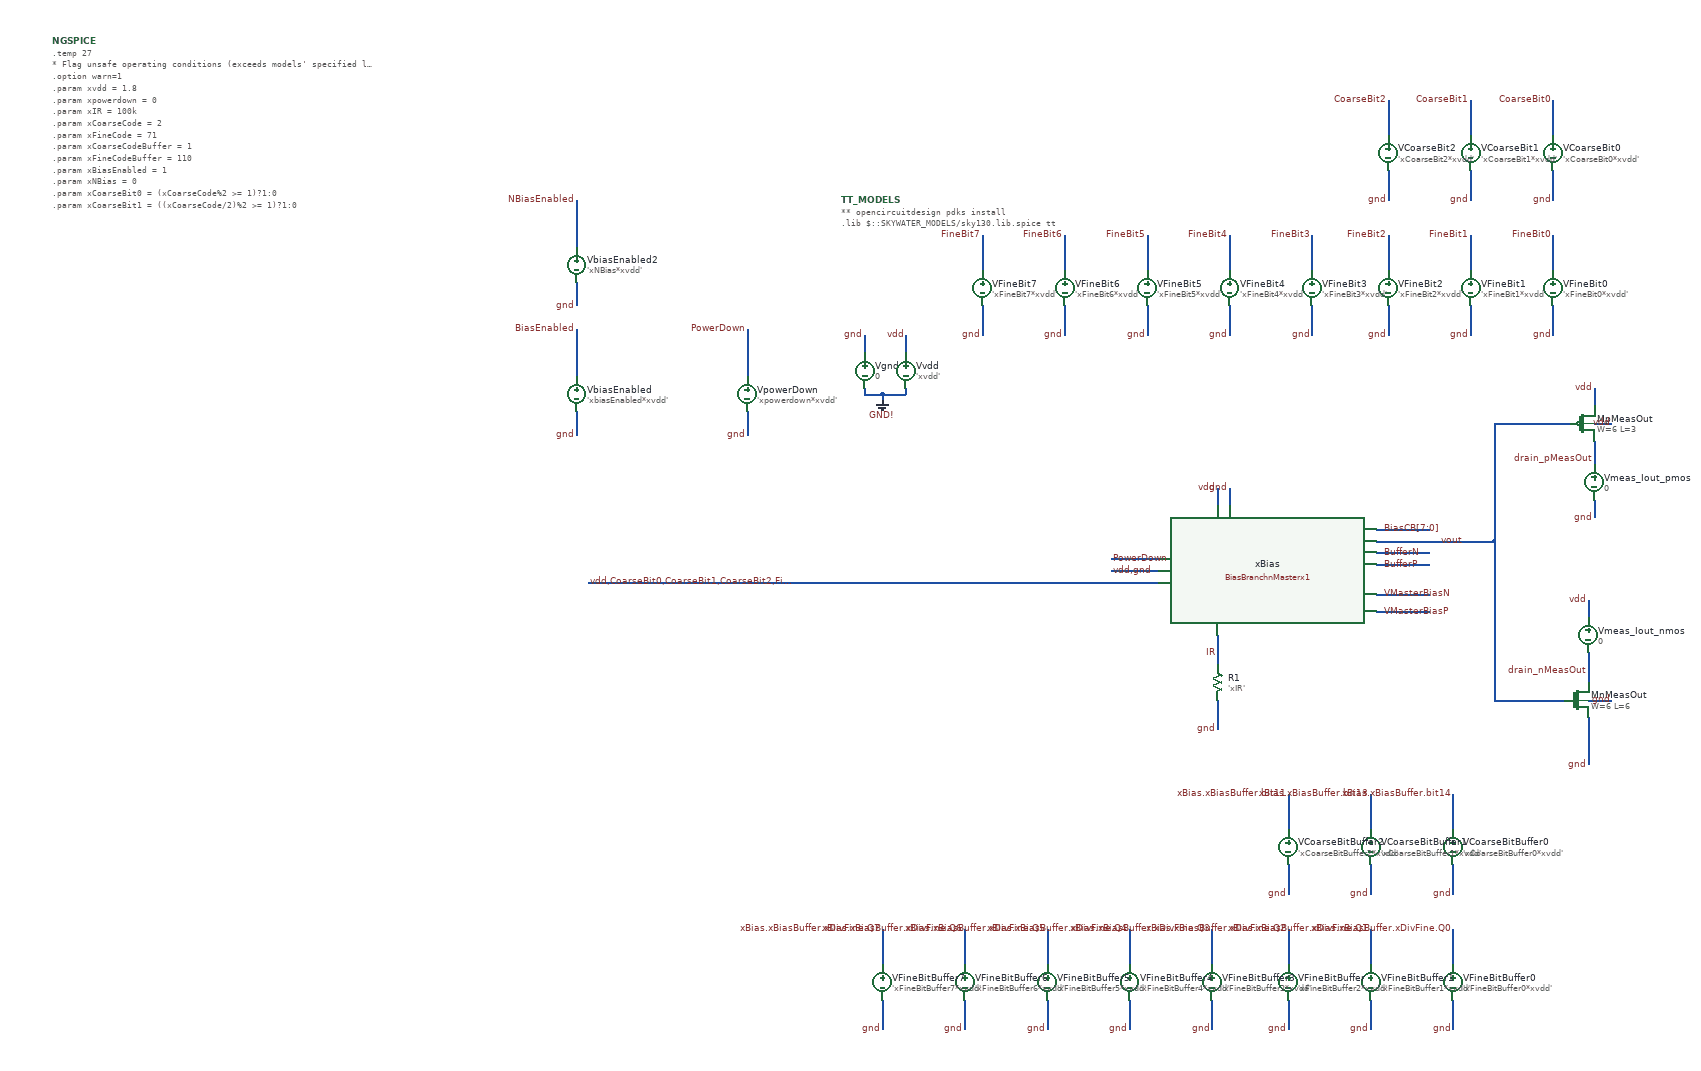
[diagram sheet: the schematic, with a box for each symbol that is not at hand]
v {xschem version=3.4.8RC file_version=1.3}
G {}
K {}
V {}
S {}
F {}
E {}
N 1250 -890 1250 -880 {lab=GND!}
N 1210 -880 1250 -880 {lab=GND!}
N 1180 -890 1180 -880 {lab=GND!}
N 1210 -880 1210 -870 {lab=GND!}
N 1180 -880 1210 -880 {lab=GND!}
N 1180 -980 1180 -950 {lab=gnd}
N 1250 -980 1250 -950 {lab=vdd}
N 980 -850 980 -810 {lab=gnd}
N 980 -990 980 -910 {lab=PowerDown}
N 2350 -1260 2350 -1210 {lab=gnd}
N 2350 -1380 2350 -1320 {lab=CoarseBit0}
N 2210 -1260 2210 -1210 {lab=gnd}
N 2210 -1380 2210 -1320 {lab=CoarseBit1}
N 2070 -1260 2070 -1210 {lab=gnd}
N 2070 -1380 2070 -1320 {lab=CoarseBit2}
N 2410 -360 2450 -360 {lab=gnd}
N 2410 -330 2410 -250 {lab=gnd}
N 2050 -630 2250 -630 {lab=vout}
N 2250 -630 2250 -360 {lab=vout}
N 2250 -360 2370 -360 {lab=vout}
N 2410 -440 2410 -390 {lab=drain_nMeasOut}
N 2410 -530 2410 -500 {lab=vdd}
N 2250 -830 2250 -630 {lab=vout}
N 2250 -830 2380 -830 {lab=vout}
N 2420 -700 2420 -670 {lab=gnd}
N 2420 -800 2420 -760 {lab=drain_pMeasOut}
N 2420 -890 2420 -860 {lab=vdd}
N 2420 -830 2450 -830 {lab=vdd}
N 1780 -720 1780 -690 {lab=vdd}
N 1800 -720 1800 -690 {lab=gnd}
N 690 -850 690 -810 {lab=gnd}
N 690 -990 690 -910 {lab=BiasEnabled}
N 690 -1070 690 -1030 {lab=gnd}
N 690 -1210 690 -1130 {lab=NBiasEnabled}
N 2050 -650 2140 -650 {lab=BiasCB[7:0]}
N 2050 -610 2140 -610 {lab=BufferN}
N 2050 -590 2140 -590 {lab=BufferP}
N 2050 -540 2140 -540 {lab=VMasterBiasN}
N 2050 -510 2140 -510 {lab=VMasterBiasP}
N 1600 -600 1680 -600 {lab=PowerDown}
N 1600 -580 1680 -580 {lab=vdd,gnd}
N 1780 -470 1780 -420 {lab=IR}
N 1780 -360 1780 -310 {lab=gnd}
N 2350 -1030 2350 -980 {lab=gnd}
N 2350 -1150 2350 -1090 {lab=FineBit0}
N 2210 -1030 2210 -980 {lab=gnd}
N 2210 -1150 2210 -1090 {lab=FineBit1}
N 2070 -1030 2070 -980 {lab=gnd}
N 2070 -1150 2070 -1090 {lab=FineBit2}
N 1940 -1030 1940 -980 {lab=gnd}
N 1940 -1150 1940 -1090 {lab=FineBit3}
N 1800 -1030 1800 -980 {lab=gnd}
N 1800 -1150 1800 -1090 {lab=FineBit4}
N 1660 -1030 1660 -980 {lab=gnd}
N 1660 -1150 1660 -1090 {lab=FineBit5}
N 1520 -1030 1520 -980 {lab=gnd}
N 1520 -1150 1520 -1090 {lab=FineBit6}
N 1380 -1030 1380 -980 {lab=gnd}
N 1380 -1150 1380 -1090 {lab=FineBit7}
N 710 -560 1680 -560 {lab=vdd,CoarseBit0,CoarseBit1,CoarseBit2,FineBit7,FineBit6,FineBit5,FineBit4,FineBit3,FineBit2,FineBit1,FineBit0,gnd,gnd,NBiasEnabled,BiasEnabled}
N 2180 -80 2180 -30 {lab=gnd}
N 2180 -200 2180 -140 {lab=xBias.xBiasBuffer.bit14}
N 2040 -80 2040 -30 {lab=gnd}
N 2040 -200 2040 -140 {lab=xBias.xBiasBuffer.bit13}
N 1900 -80 1900 -30 {lab=gnd}
N 1900 -200 1900 -140 {lab=xBias.xBiasBuffer.bit11}
N 2180 150 2180 200 {lab=gnd}
N 2180 30 2180 90 {lab=xBias.xBiasBuffer.xDivFine.Q0}
N 2040 150 2040 200 {lab=gnd}
N 2040 30 2040 90 {lab=xBias.xBiasBuffer.xDivFine.Q1}
N 1900 150 1900 200 {lab=gnd}
N 1900 30 1900 90 {lab=xBias.xBiasBuffer.xDivFine.Q2}
N 1770 150 1770 200 {lab=gnd}
N 1770 30 1770 90 {lab=xBias.xBiasBuffer.xDivFine.Q3}
N 1630 150 1630 200 {lab=gnd}
N 1630 30 1630 90 {lab=xBias.xBiasBuffer.xDivFine.Q4}
N 1490 150 1490 200 {lab=gnd}
N 1490 30 1490 90 {lab=xBias.xBiasBuffer.xDivFine.Q5}
N 1350 150 1350 200 {lab=gnd}
N 1350 30 1350 90 {lab=xBias.xBiasBuffer.xDivFine.Q6}
N 1210 150 1210 200 {lab=gnd}
N 1210 30 1210 90 {lab=xBias.xBiasBuffer.xDivFine.Q7}
C {vsource.sym} 1180 -920 0 0 {name=Vgnd value=0 savecurrent=true}
C {gnd.sym} 1210 -870 0 0 {name=l1 lab=GND!}
C {vsource.sym} 1250 -920 0 0 {name=Vvdd value='xvdd' savecurrent=true}
C {lab_wire.sym} 1180 -980 3 0 {name=p1 sig_type=std_logic lab=gnd}
C {lab_wire.sym} 1250 -980 3 0 {name=p4 sig_type=std_logic lab=vdd}
C {vsource.sym} 980 -880 0 0 {name=VpowerDown value='xpowerdown*xvdd' savecurrent=true}
C {lab_wire.sym} 980 -810 3 1 {name=p7 sig_type=std_logic lab=gnd}
C {lab_wire.sym} 980 -990 3 0 {name=p8 sig_type=std_logic lab=PowerDown}
C {devices/code.sym} 1140 -1210 0 0 {name=TT_MODELS
only_toplevel=true
format="tcleval( @value )"
value="
** opencircuitdesign pdks install
.lib $::SKYWATER_MODELS/sky130.lib.spice tt
"
spice_ignore=false}
C {devices/launcher.sym} 1120 -1340 2 1 {name=h1
descr="Annotate OP" 
tclcommand="set show_hidden_texts 1; xschem annotate_op"
}
C {code_shown.sym} -200 -1480 0 0 {name=NGSPICE
only_toplevel=true
value="

.temp 27

* Flag unsafe operating conditions (exceeds models' specified limits)
.option warn=1

.param xvdd = 1.8
.param xpowerdown = 0
.param xIR = 100k

.param xCoarseCode = 2
.param xFineCode = 71
.param xCoarseCodeBuffer = 1
.param xFineCodeBuffer = 110


.param xBiasEnabled = 1
.param xNBias = 0

.param xCoarseBit0 = (xCoarseCode%2 >= 1)?1:0
.param xCoarseBit1 = ((xCoarseCode/2)%2 >= 1)?1:0
.param xCoarseBit2 = ((xCoarseCode/4)%2 >= 1)?1:0
.param xFineBit0 = (xFineCode%2 >= 1)?1:0
.param xFineBit1 = ((xFineCode/2)%2 >= 1)?1:0
.param xFineBit2 = ((xFineCode/4)%2 >= 1)?1:0
.param xFineBit3 = ((xFineCode/8)%2 >= 1)?1:0
.param xFineBit4 = ((xFineCode/16)%2 >= 1)?1:0
.param xFineBit5 = ((xFineCode/32)%2 >= 1)?1:0
.param xFineBit6 = ((xFineCode/64)%2 >= 1)?1:0
.param xFineBit7 = ((xFineCode/128)%2 >= 1)?1:0

.param xCoarseBitBuffer0 = (xCoarseCodeBuffer%2 >= 1)?1:0
.param xCoarseBitBuffer1 = ((xCoarseCodeBuffer/2)%2 >= 1)?1:0
.param xCoarseBitBuffer2 = ((xCoarseCodeBuffer/4)%2 >= 1)?1:0
.param xFineBitBuffer0 = (xFineCodeBuffer%2 >= 1)?1:0
.param xFineBitBuffer1 = ((xFineCodeBuffer/2)%2 >= 1)?1:0
.param xFineBitBuffer2 = ((xFineCodeBuffer/4)%2 >= 1)?1:0
.param xFineBitBuffer3 = ((xFineCodeBuffer/8)%2 >= 1)?1:0
.param xFineBitBuffer4 = ((xFineCodeBuffer/16)%2 >= 1)?1:0
.param xFineBitBuffer5 = ((xFineCodeBuffer/32)%2 >= 1)?1:0
.param xFineBitBuffer6 = ((xFineCodeBuffer/64)%2 >= 1)?1:0
.param xFineBitBuffer7 = ((xFineCodeBuffer/128)%2 >= 1)?1:0

*.nodeset v(xBias.xBiasBuffer.bit14) = 'xCoarseBitBuffer0*xvdd'
*.nodeset v(xBias.xBiasBuffer.bit13) = 'xCoarseBitBuffer1*xvdd'
*.nodeset v(xBias.xBiasBuffer.bit12) = 'xCoarseBitBuffer0*xvdd'
*.nodeset v(xBias.xBiasBuffer.xDivFine.Q7) = 'xFineBitBuffer7*xvdd'
*.nodeset v(xBias.xBiasBuffer.xDivFine.Q6) = 'xFineBitBuffer6*xvdd'
*.nodeset v(xBias.xBiasBuffer.xDivFine.Q5) = 'xFineBitBuffer5*xvdd'
*.nodeset v(xBias.xBiasBuffer.xDivFine.Q4) = 'xFineBitBuffer4*xvdd'
*.nodeset v(xBias.xBiasBuffer.xDivFine.Q3) = 'xFineBitBuffer3*xvdd'
*.nodeset v(xBias.xBiasBuffer.xDivFine.Q2) = 'xFineBitBuffer2*xvdd'
*.nodeset v(xBias.xBiasBuffer.xDivFine.Q1) = 'xFineBitBuffer1*xvdd'
*.nodeset v(xBias.xBiasBuffer.xDivFine.Q0) = 'xFineBitBuffer0*xvdd'



.save v(@m.xBias.xBiasMasternCoarse.xBiasMasterBias.xMNBias.msky130_fd_pr__nfet_01v8_lvt[vdsat])
.save @m.xBias.xBiasMasternCoarse.xBiasMasterBias.xMNBias.msky130_fd_pr__nfet_01v8_lvt[id]
.save v(@m.xBias.xBiasMasternCoarse.xBiasMasterBias.xMNBiasDio.msky130_fd_pr__nfet_01v8_lvt[vdsat])
.save @m.xBias.xBiasMasternCoarse.xBiasMasterBias.xMNBiasDio.msky130_fd_pr__nfet_01v8_lvt[id]
.save v(@m.xBias.xBiasMasternCoarse.xBiasMasterBias.xMNBiasCascDio.msky130_fd_pr__nfet_01v8_lvt[vdsat])
.save v(@m.xBias.xBiasMasternCoarse.xBiasMasterBias.xMNBiasCasc.msky130_fd_pr__nfet_01v8_lvt[vdsat])
.save v(@m.xBias.xBiasMasternCoarse.xBiasMasterBias.xMPBias.msky130_fd_pr__pfet_01v8_lvt[vdsat])
.save v(@m.xBias.xBiasMasternCoarse.xBiasMasterBias.xMPBiasDio.msky130_fd_pr__pfet_01v8_lvt[vdsat])
.save v(@m.xBias.xBiasMasternCoarse.xBiasMasterBias.xMNMirr1.msky130_fd_pr__nfet_01v8_lvt[vdsat])
.save @m.xBias.xBiasMasternCoarse.xBiasMasterBias.xMNMirr1.msky130_fd_pr__nfet_01v8_lvt[id]
.save v(@m.xBias.xBiasMasternCoarse.xBiasMasterBias.xMNMirr2.msky130_fd_pr__nfet_01v8_lvt[vdsat])
.save @m.xBias.xBiasMasternCoarse.xBiasMasterBias.xMNMirr2.msky130_fd_pr__nfet_01v8_lvt[id]
.save v(@m.xBias.xBiasMasternCoarse.xBiasMasterBias.xMNMirrCasc1.msky130_fd_pr__nfet_01v8_lvt[vdsat])
.save v(@m.xBias.xBiasMasternCoarse.xBiasMasterBias.xMNMirrCasc2.msky130_fd_pr__nfet_01v8_lvt[vdsat])
.save @m.xBias.xBiasMasternCoarse.xMBDiv.xMNDioCB0.msky130_fd_pr__nfet_01v8_lvt[id]
.save @m.xBias.xBiasMasternCoarse.xMBDiv.xMNDioCB1.msky130_fd_pr__nfet_01v8_lvt[id]
.save @m.xBias.xBiasMasternCoarse.xMBDiv.xMNDioCB2.msky130_fd_pr__nfet_01v8_lvt[id]
.save @m.xBias.xBiasMasternCoarse.xMBDiv.xMNDioCB3.msky130_fd_pr__nfet_01v8_lvt[id]
.save @m.xBias.xBiasMasternCoarse.xMBDiv.xMNDioCB4.msky130_fd_pr__nfet_01v8_lvt[id]
.save @m.xBias.xBiasMasternCoarse.xMBDiv.xMNDioCB5.msky130_fd_pr__nfet_01v8_lvt[id]
.save @m.xBias.xBiasMasternCoarse.xMBDiv.xMNDioCB6.msky130_fd_pr__nfet_01v8_lvt[id]
.save @m.xBias.xBiasMasternCoarse.xMBDiv.xMNDioCB7.msky130_fd_pr__nfet_01v8_lvt[id]
.save @m.xBias.xBiasBranch.xCoarseBuf.xSel.xMmirrB0.msky130_fd_pr__nfet_01v8_lvt[id]
.save @m.xBias.xBiasBranch.xCoarseBuf.xSel.xMmirrB1.msky130_fd_pr__nfet_01v8_lvt[id]
.save @m.xBias.xBiasBranch.xCoarseBuf.xSel.xMmirrhB2.msky130_fd_pr__nfet_01v8_lvt[id]
.save @m.xBias.xBiasBranch.xCoarseBuf.xSel.xMmirrhB3.msky130_fd_pr__nfet_01v8_lvt[id]
.save @m.xBias.xBiasBranch.xCoarseBuf.xSel.xMmirrhB4t07.msky130_fd_pr__nfet_01v8_lvt[id]
.save v(@m.xBias.xBiasBranch.xCoarseBuf.xSel.xMmirrB0.msky130_fd_pr__nfet_01v8_lvt[vdsat])
.save v(@m.xBias.xBiasBranch.xCoarseBuf.xSel.xMmirrB1.msky130_fd_pr__nfet_01v8_lvt[vdsat])
.save v(@m.xBias.xBiasBranch.xCoarseBuf.xSel.xMmirrhB2.msky130_fd_pr__nfet_01v8_lvt[vdsat])
.save v(@m.xBias.xBiasBranch.xCoarseBuf.xSel.xMmirrhB3.msky130_fd_pr__nfet_01v8_lvt[vdsat])
.save v(@m.xBias.xBiasBranch.xCoarseBuf.xSel.xMmirrhB4t07.msky130_fd_pr__nfet_01v8_lvt[vdsat])
.save @m.xBias.xBiasBranch.xCoarse2Fine.xMpDioOut.msky130_fd_pr__pfet_01v8_lvt[id]
.save @m.xBias.xBiasBranch.xCoarse2Fine.xMpMirrOut.msky130_fd_pr__pfet_01v8_lvt[id]
.save @m.xBias.xBiasBranch.xCoarse2Fine.xMpDionOut2.msky130_fd_pr__pfet_01v8_lvt[id]
.save @m.xBias.xBiasBranch.xCoarse2Fine.xMpMirrnOut2.msky130_fd_pr__pfet_01v8_lvt[id]
.save v(@m.xBias.xBiasBranch.xCoarse2Fine.xMpDioOut.msky130_fd_pr__pfet_01v8_lvt[vdsat])
.save v(@m.xBias.xBiasBranch.xCoarse2Fine.xMpMirrOut.msky130_fd_pr__pfet_01v8_lvt[vdsat])
.save v(@m.xBias.xBiasBranch.xCoarse2Fine.xMpDionOut2.msky130_fd_pr__pfet_01v8_lvt[vdsat])
.save v(@m.xBias.xBiasBranch.xCoarse2Fine.xMpMirrnOut2.msky130_fd_pr__pfet_01v8_lvt[vdsat])
.save @m.xBias.xBiasBranch.xCoarse2Fine.xMpInDio.msky130_fd_pr__pfet_01v8_lvt[id]
.save @m.xBias.xBiasBranch.xBuffs.xMnDio.msky130_fd_pr__nfet_01v8[id]
.save @m.xBias.xBiasBranch.xBuffs.xMnMirr.msky130_fd_pr__nfet_01v8[id]
.save @m.xBias.xBiasBranch.xBuffs.xMnMirrBuffBias.msky130_fd_pr__nfet_01v8_lvt[id]
.save @m.xBias.xBiasBranch.xBuffs.xMnMirrBuffB0.msky130_fd_pr__nfet_01v8_lvt[id]
.save @m.xBias.xBiasBranch.xBuffs.xMnMirrBuffnB0.msky130_fd_pr__nfet_01v8_lvt[id]
.save v(@m.xBias.xBiasBranch.xBuffs.xMnDio.msky130_fd_pr__nfet_01v8[vdsat])
.save v(@m.xBias.xBiasBranch.xBuffs.xMnMirr.msky130_fd_pr__nfet_01v8[vdsat])
.save v(@m.xBias.xBiasBranch.xBuffs.xMnMirrBuffBias.msky130_fd_pr__nfet_01v8_lvt[vdsat])
.save v(@m.xBias.xBiasBranch.xBuffs.xMnMirrBuffB0.msky130_fd_pr__nfet_01v8_lvt[vdsat])
.save v(@m.xBias.xBiasBranch.xBuffs.xMnMirrBuffnB0.msky130_fd_pr__nfet_01v8_lvt[vdsat])
.save @m.xBias.xBiasBranch.xBuffs.xMpDio.msky130_fd_pr__pfet_01v8[id]
.save @m.xBias.xBiasBranch.xBuffs.xMpMirrBuffBias.msky130_fd_pr__pfet_01v8_lvt[id]
.save @m.xBias.xBiasBranch.xBuffs.xMpMirrBuffB0.msky130_fd_pr__pfet_01v8_lvt[id]
.save @m.xBias.xBiasBranch.xBuffs.xMpMirrBuffnB0.msky130_fd_pr__pfet_01v8_lvt[id]
.save v(@m.xBias.xBiasBranch.xBuffs.xMpDio.msky130_fd_pr__pfet_01v8[vdsat])
.save v(@m.xBias.xBiasBranch.xBuffs.xMpMirrBuffBias.msky130_fd_pr__pfet_01v8_lvt[vdsat])
.save v(@m.xBias.xBiasBranch.xBuffs.xMpMirrBuffB0.msky130_fd_pr__pfet_01v8_lvt[vdsat])
.save v(@m.xBias.xBiasBranch.xBuffs.xMpMirrBuffnB0.msky130_fd_pr__pfet_01v8_lvt[vdsat])
.save @m.xBias.xBiasBuffer.xCoarseBuf.xSel.xMmirrB0.msky130_fd_pr__nfet_01v8_lvt[id]
.save @m.xBias.xBiasBuffer.xCoarseBuf.xSel.xMmirrB1.msky130_fd_pr__nfet_01v8_lvt[id]
.save @m.xBias.xBiasBuffer.xCoarseBuf.xSel.xMmirrhB2.msky130_fd_pr__nfet_01v8_lvt[id]
.save @m.xBias.xBiasBuffer.xCoarseBuf.xSel.xMmirrhB3.msky130_fd_pr__nfet_01v8_lvt[id]
.save @m.xBias.xBiasBuffer.xCoarseBuf.xSel.xMmirrhB4t07.msky130_fd_pr__nfet_01v8_lvt[id]
.save v(@m.xBias.xBiasBuffer.xCoarseBuf.xSel.xMmirrB0.msky130_fd_pr__nfet_01v8_lvt[vdsat])
.save v(@m.xBias.xBiasBuffer.xCoarseBuf.xSel.xMmirrB1.msky130_fd_pr__nfet_01v8_lvt[vdsat])
.save v(@m.xBias.xBiasBuffer.xCoarseBuf.xSel.xMmirrhB2.msky130_fd_pr__nfet_01v8_lvt[vdsat])
.save v(@m.xBias.xBiasBuffer.xCoarseBuf.xSel.xMmirrhB3.msky130_fd_pr__nfet_01v8_lvt[vdsat])
.save v(@m.xBias.xBiasBuffer.xCoarseBuf.xSel.xMmirrhB4t07.msky130_fd_pr__nfet_01v8_lvt[vdsat])
.save @m.xBias.xBiasBuffer.xCoarse2Fine.xMpDioOut.msky130_fd_pr__pfet_01v8_lvt[id]
.save @m.xBias.xBiasBuffer.xCoarse2Fine.xMpMirrOut.msky130_fd_pr__pfet_01v8_lvt[id]
.save @m.xBias.xBiasBuffer.xCoarse2Fine.xMpDionOut2.msky130_fd_pr__pfet_01v8_lvt[id]
.save @m.xBias.xBiasBuffer.xCoarse2Fine.xMpMirrnOut2.msky130_fd_pr__pfet_01v8_lvt[id]
.save v(@m.xBias.xBiasBuffer.xCoarse2Fine.xMpDioOut.msky130_fd_pr__pfet_01v8_lvt[vdsat])
.save v(@m.xBias.xBiasBuffer.xCoarse2Fine.xMpMirrOut.msky130_fd_pr__pfet_01v8_lvt[vdsat])
.save v(@m.xBias.xBiasBuffer.xCoarse2Fine.xMpDionOut2.msky130_fd_pr__pfet_01v8_lvt[vdsat])
.save v(@m.xBias.xBiasBuffer.xCoarse2Fine.xMpMirrnOut2.msky130_fd_pr__pfet_01v8_lvt[vdsat])
.save @m.xBias.xBiasBuffer.xCoarse2Fine.xMpInDio.msky130_fd_pr__pfet_01v8_lvt[id]
.save @m.xBias.xBiasBuffer.xMnDio.msky130_fd_pr__nfet_01v8_lvt[id]
.save @m.xBias.xBiasBuffer.xMnMirr.msky130_fd_pr__nfet_01v8_lvt[id]
.save @m.xBias.xBiasBuffer.xMpDio.msky130_fd_pr__pfet_01v8_lvt[id]
.save v(@m.xBias.xBiasBuffer.xMnDio.msky130_fd_pr__nfet_01v8_lvt[vdsat])
.save v(@m.xBias.xBiasBuffer.xMnMirr.msky130_fd_pr__nfet_01v8_lvt[vdsat])
.save v(@m.xBias.xBiasBuffer.xMpDio.msky130_fd_pr__pfet_01v8_lvt[vdsat])


.save all

.op
"}
C {vsource.sym} 2350 -1290 0 0 {name=VCoarseBit0 value='xCoarseBit0*xvdd' savecurrent=true}
C {lab_wire.sym} 2350 -1210 3 1 {name=p27 sig_type=std_logic lab=gnd}
C {lab_wire.sym} 2350 -1380 1 1 {name=p28 sig_type=std_logic lab=CoarseBit0}
C {vsource.sym} 2210 -1290 0 0 {name=VCoarseBit1 value='xCoarseBit1*xvdd' savecurrent=true}
C {lab_wire.sym} 2210 -1210 3 1 {name=p29 sig_type=std_logic lab=gnd}
C {lab_wire.sym} 2210 -1380 1 1 {name=p30 sig_type=std_logic lab=CoarseBit1}
C {vsource.sym} 2070 -1290 0 0 {name=VCoarseBit2 value='xCoarseBit2*xvdd' savecurrent=true}
C {lab_wire.sym} 2070 -1210 3 1 {name=p31 sig_type=std_logic lab=gnd}
C {lab_wire.sym} 2070 -1380 1 1 {name=p32 sig_type=std_logic lab=CoarseBit2}
C {sky130_fd_pr/nfet_01v8.sym} 2390 -360 0 0 {name=MnMeasOut
W=6
L=6
nf=1 
mult=1
ad="expr('int((@nf + 1)/2) * @W / @nf * 0.29')"
pd="expr('2*int((@nf + 1)/2) * (@W / @nf + 0.29)')"
as="expr('int((@nf + 2)/2) * @W / @nf * 0.29')"
ps="expr('2*int((@nf + 2)/2) * (@W / @nf + 0.29)')"
nrd="expr('0.29 / @W ')" nrs="expr('0.29 / @W ')"
sa=0 sb=0 sd=0
model=nfet_01v8
spiceprefix=X
}
C {lab_wire.sym} 2450 -360 2 1 {name=p42 sig_type=std_logic lab=gnd}
C {lab_wire.sym} 2410 -250 3 1 {name=p43 sig_type=std_logic lab=gnd}
C {vsource.sym} 2410 -470 0 1 {name=Vmeas_Iout_nmos value=0 savecurrent=true}
C {lab_wire.sym} 2410 -530 1 1 {name=p44 sig_type=std_logic lab=vdd}
C {sky130_fd_pr/pfet_01v8.sym} 2400 -830 0 0 {name=MpMeasOut
W=6
L=3
nf=1
mult=2
ad="expr('int((@nf + 1)/2) * @W / @nf * 0.29')"
pd="expr('2*int((@nf + 1)/2) * (@W / @nf + 0.29)')"
as="expr('int((@nf + 2)/2) * @W / @nf * 0.29')"
ps="expr('2*int((@nf + 2)/2) * (@W / @nf + 0.29)')"
nrd="expr('0.29 / @W ')" nrs="expr('0.29 / @W ')"
sa=0 sb=0 sd=0
model=pfet_01v8
spiceprefix=X
}
C {vsource.sym} 2420 -730 0 1 {name=Vmeas_Iout_pmos value=0 savecurrent=true}
C {lab_wire.sym} 2420 -670 3 1 {name=p45 sig_type=std_logic lab=gnd}
C {lab_wire.sym} 2420 -890 1 1 {name=p46 sig_type=std_logic lab=vdd}
C {lab_wire.sym} 2450 -830 2 1 {name=p47 sig_type=std_logic lab=vdd}
C {lab_wire.sym} 2420 -770 3 1 {name=p48 sig_type=std_logic lab=drain_pMeasOut}
C {lab_wire.sym} 1780 -720 3 0 {name=p59 sig_type=std_logic lab=vdd}
C {lab_wire.sym} 1800 -720 3 0 {name=p61 sig_type=std_logic lab=gnd}
C {vsource.sym} 690 -880 0 0 {name=VbiasEnabled value='xbiasEnabled*xvdd' savecurrent=false}
C {lab_wire.sym} 690 -810 3 1 {name=VbiasEnabled1 sig_type=std_logic lab=gnd
value='(1-xbiasEnabled)*xvdd'
savecurrent=false}
C {lab_wire.sym} 690 -990 3 0 {name=p2 sig_type=std_logic lab=BiasEnabled}
C {vsource.sym} 690 -1100 0 0 {name=VbiasEnabled2 value='xNBias*xvdd' savecurrent=false}
C {lab_wire.sym} 690 -1030 3 1 {name=VbiasEnabled5 sig_type=std_logic lab=gnd
value='(1-xbiasEnabled)*xvdd'
savecurrent=false}
C {lab_wire.sym} 690 -1210 3 0 {name=p5 sig_type=std_logic lab=NBiasEnabled}
C {lab_wire.sym} 2200 -630 0 0 {name=p10 sig_type=std_logic lab=vout}
C {lab_wire.sym} 2410 -410 3 1 {name=p11 sig_type=std_logic lab=drain_nMeasOut}
C {BiasBranchnMasterx1.sym} 1520 -560 0 0 {name=xBias}
C {noconn.sym} 2140 -650 2 0 {name=l3[7:0]}
C {lab_wire.sym} 2060 -650 0 1 {name=p12 sig_type=std_logic lab=BiasCB[7:0]}
C {noconn.sym} 2140 -610 2 0 {name=l2}
C {noconn.sym} 2140 -590 2 0 {name=l3}
C {noconn.sym} 2140 -540 2 0 {name=l4}
C {noconn.sym} 2140 -510 2 0 {name=l5}
C {lab_wire.sym} 2060 -610 0 1 {name=p13 sig_type=std_logic lab=BufferN}
C {lab_wire.sym} 2060 -590 0 1 {name=p14 sig_type=std_logic lab=BufferP}
C {lab_wire.sym} 2060 -540 0 1 {name=p15 sig_type=std_logic lab=VMasterBiasN}
C {lab_wire.sym} 2060 -510 0 1 {name=p16 sig_type=std_logic lab=VMasterBiasP}
C {lab_wire.sym} 1600 -600 0 1 {name=p9 sig_type=std_logic lab=PowerDown}
C {lab_wire.sym} 1600 -580 0 1 {name=p17 sig_type=std_logic lab=vdd,gnd}
C {res.sym} 1780 -390 0 0 {name=R1
value='xIR'
footprint=1206
device=resistor
m=1}
C {lab_wire.sym} 1780 -310 3 1 {name=p18 sig_type=std_logic lab=gnd}
C {lab_wire.sym} 1780 -440 3 1 {name=p19 sig_type=std_logic lab=IR}
C {vsource.sym} 2350 -1060 0 0 {name=VFineBit0 value='xFineBit0*xvdd' savecurrent=true}
C {lab_wire.sym} 2350 -980 3 1 {name=p20 sig_type=std_logic lab=gnd}
C {lab_wire.sym} 2350 -1150 1 1 {name=p21 sig_type=std_logic lab=FineBit0}
C {vsource.sym} 2210 -1060 0 0 {name=VFineBit1 value='xFineBit1*xvdd' savecurrent=true}
C {lab_wire.sym} 2210 -980 3 1 {name=p22 sig_type=std_logic lab=gnd}
C {lab_wire.sym} 2210 -1150 1 1 {name=p23 sig_type=std_logic lab=FineBit1}
C {vsource.sym} 2070 -1060 0 0 {name=VFineBit2 value='xFineBit2*xvdd' savecurrent=true}
C {lab_wire.sym} 2070 -980 3 1 {name=p24 sig_type=std_logic lab=gnd}
C {lab_wire.sym} 2070 -1150 1 1 {name=p25 sig_type=std_logic lab=FineBit2}
C {vsource.sym} 1940 -1060 0 0 {name=VFineBit3 value='xFineBit3*xvdd' savecurrent=true}
C {lab_wire.sym} 1940 -980 3 1 {name=p26 sig_type=std_logic lab=gnd}
C {lab_wire.sym} 1940 -1150 1 1 {name=p33 sig_type=std_logic lab=FineBit3}
C {vsource.sym} 1800 -1060 0 0 {name=VFineBit4 value='xFineBit4*xvdd' savecurrent=true}
C {lab_wire.sym} 1800 -980 3 1 {name=p34 sig_type=std_logic lab=gnd}
C {lab_wire.sym} 1800 -1150 1 1 {name=p35 sig_type=std_logic lab=FineBit4}
C {vsource.sym} 1660 -1060 0 0 {name=VFineBit5 value='xFineBit5*xvdd' savecurrent=true}
C {lab_wire.sym} 1660 -980 3 1 {name=p36 sig_type=std_logic lab=gnd}
C {lab_wire.sym} 1660 -1150 1 1 {name=p37 sig_type=std_logic lab=FineBit5}
C {vsource.sym} 1520 -1060 0 0 {name=VFineBit6 value='xFineBit6*xvdd' savecurrent=true}
C {lab_wire.sym} 1520 -980 3 1 {name=p41 sig_type=std_logic lab=gnd}
C {lab_wire.sym} 1520 -1150 1 1 {name=p49 sig_type=std_logic lab=FineBit6}
C {vsource.sym} 1380 -1060 0 0 {name=VFineBit7 value='xFineBit7*xvdd' savecurrent=true}
C {lab_wire.sym} 1380 -980 3 1 {name=p50 sig_type=std_logic lab=gnd}
C {lab_wire.sym} 1380 -1150 1 1 {name=p51 sig_type=std_logic lab=FineBit7}
C {lab_wire.sym} 710 -560 0 1 {name=p3 sig_type=std_logic lab=vdd,CoarseBit0,CoarseBit1,CoarseBit2,FineBit7,FineBit6,FineBit5,FineBit4,FineBit3,FineBit2,FineBit1,FineBit0,gnd,gnd,NBiasEnabled,BiasEnabled}
C {vsource.sym} 2180 -110 0 0 {name=VCoarseBitBuffer0 value='xCoarseBitBuffer0*xvdd' savecurrent=true}
C {lab_wire.sym} 2180 -30 3 1 {name=p6 sig_type=std_logic lab=gnd}
C {lab_wire.sym} 2180 -200 1 1 {name=p38 sig_type=std_logic lab=xBias.xBiasBuffer.bit14}
C {vsource.sym} 2040 -110 0 0 {name=VCoarseBitBuffer1 value='xCoarseBitBuffer1*xvdd' savecurrent=true}
C {lab_wire.sym} 2040 -30 3 1 {name=p39 sig_type=std_logic lab=gnd}
C {lab_wire.sym} 2040 -200 1 1 {name=p40 sig_type=std_logic lab=xBias.xBiasBuffer.bit13}
C {vsource.sym} 1900 -110 0 0 {name=VCoarseBitBuffer2 value='xCoarseBitBuffer2*xvdd' savecurrent=true}
C {lab_wire.sym} 1900 -30 3 1 {name=p52 sig_type=std_logic lab=gnd}
C {lab_wire.sym} 1900 -200 1 1 {name=p53 sig_type=std_logic lab=xBias.xBiasBuffer.bit11}
C {vsource.sym} 2180 120 0 0 {name=VFineBitBuffer0 value='xFineBitBuffer0*xvdd' savecurrent=true}
C {lab_wire.sym} 2180 200 3 1 {name=p54 sig_type=std_logic lab=gnd}
C {lab_wire.sym} 2180 30 1 1 {name=p55 sig_type=std_logic lab=xBias.xBiasBuffer.xDivFine.Q0}
C {vsource.sym} 2040 120 0 0 {name=VFineBitBuffer1 value='xFineBitBuffer1*xvdd' savecurrent=true}
C {lab_wire.sym} 2040 200 3 1 {name=p56 sig_type=std_logic lab=gnd}
C {lab_wire.sym} 2040 30 1 1 {name=p57 sig_type=std_logic lab=xBias.xBiasBuffer.xDivFine.Q1}
C {vsource.sym} 1900 120 0 0 {name=VFineBitBuffer value='xFineBitBuffer2*xvdd' savecurrent=true}
C {lab_wire.sym} 1900 200 3 1 {name=p58 sig_type=std_logic lab=gnd}
C {lab_wire.sym} 1900 30 1 1 {name=p60 sig_type=std_logic lab=xBias.xBiasBuffer.xDivFine.Q2}
C {vsource.sym} 1770 120 0 0 {name=VFineBitBuffer3 value='xFineBitBuffer3*xvdd' savecurrent=true}
C {lab_wire.sym} 1770 200 3 1 {name=p62 sig_type=std_logic lab=gnd}
C {lab_wire.sym} 1770 30 1 1 {name=p63 sig_type=std_logic lab=xBias.xBiasBuffer.xDivFine.Q3}
C {vsource.sym} 1630 120 0 0 {name=VFineBitBuffer4 value='xFineBitBuffer4*xvdd' savecurrent=true}
C {lab_wire.sym} 1630 200 3 1 {name=p64 sig_type=std_logic lab=gnd}
C {lab_wire.sym} 1630 30 1 1 {name=p65 sig_type=std_logic lab=xBias.xBiasBuffer.xDivFine.Q4}
C {vsource.sym} 1490 120 0 0 {name=VFineBitBuffer5 value='xFineBitBuffer5*xvdd' savecurrent=true}
C {lab_wire.sym} 1490 200 3 1 {name=p66 sig_type=std_logic lab=gnd}
C {lab_wire.sym} 1490 30 1 1 {name=p67 sig_type=std_logic lab=xBias.xBiasBuffer.xDivFine.Q5}
C {vsource.sym} 1350 120 0 0 {name=VFineBitBuffer6 value='xFineBitBuffer6*xvdd' savecurrent=true}
C {lab_wire.sym} 1350 200 3 1 {name=p68 sig_type=std_logic lab=gnd}
C {lab_wire.sym} 1350 30 1 1 {name=p69 sig_type=std_logic lab=xBias.xBiasBuffer.xDivFine.Q6}
C {vsource.sym} 1210 120 0 0 {name=VFineBitBuffer7 value='xFineBitBuffer7*xvdd' savecurrent=true}
C {lab_wire.sym} 1210 200 3 1 {name=p70 sig_type=std_logic lab=gnd}
C {lab_wire.sym} 1210 30 1 1 {name=p71 sig_type=std_logic lab=xBias.xBiasBuffer.xDivFine.Q7}
